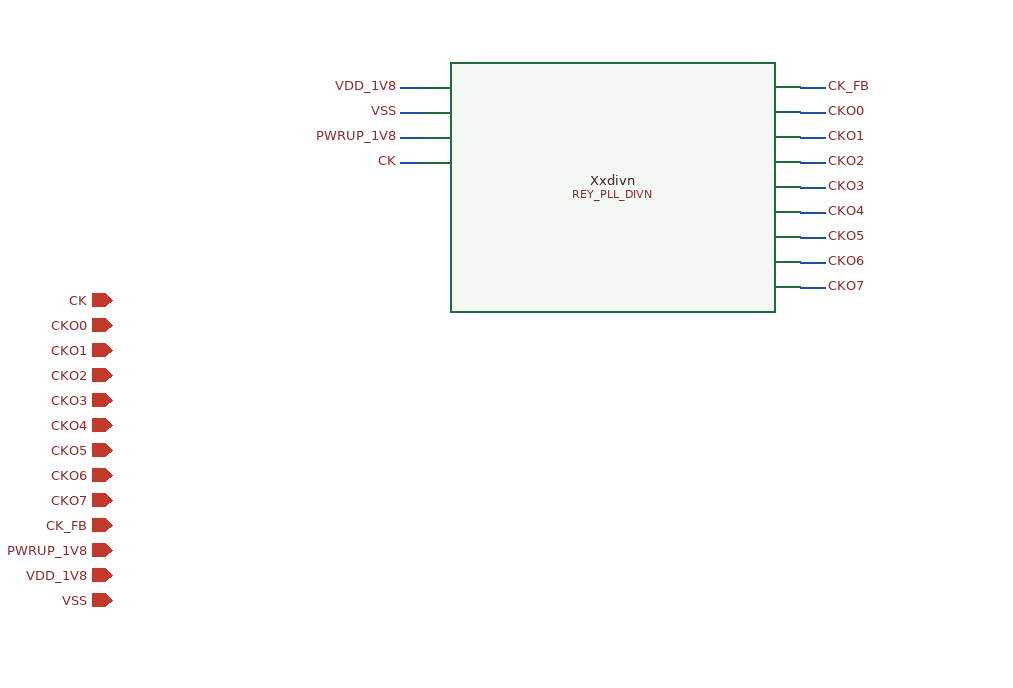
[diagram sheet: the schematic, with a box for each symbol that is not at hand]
v {xschem version=3.0.0 file_version=1.2 }
G {}
K {}
V {}
S {}
E {}
C {devices/iopin.sym} 0 0 0 0 {name=p0 lab=CK}
C {devices/iopin.sym} 0 20 0 0 {name=p1 lab=CKO0}
C {devices/iopin.sym} 0 40 0 0 {name=p2 lab=CKO1}
C {devices/iopin.sym} 0 60 0 0 {name=p3 lab=CKO2}
C {devices/iopin.sym} 0 80 0 0 {name=p4 lab=CKO3}
C {devices/iopin.sym} 0 100 0 0 {name=p5 lab=CKO4}
C {devices/iopin.sym} 0 120 0 0 {name=p6 lab=CKO5}
C {devices/iopin.sym} 0 140 0 0 {name=p7 lab=CKO6}
C {devices/iopin.sym} 0 160 0 0 {name=p8 lab=CKO7}
C {devices/iopin.sym} 0 180 0 0 {name=p9 lab=CK_FB}
C {devices/iopin.sym} 0 200 0 0 {name=p10 lab=PWRUP_1V8}
C {devices/iopin.sym} 0 220 0 0 {name=p11 lab=VDD_1V8}
C {devices/iopin.sym} 0 240 0 0 {name=p12 lab=VSS}
C {REY_PLL_SKY130A/REY_PLL_DIVN.sym} 400 0 0 0 {name=Xxdivn}
N 230.0 -170.0 250.0 -170.0 {lab=VDD_1V8}
C {devices/lab_pin.sym} 230.0 -170.0 0 0 {name=l0 sig_type=std_logic lab=VDD_1V8 }
N 230.0 -150.0 250.0 -150.0 {lab=VSS}
C {devices/lab_pin.sym} 230.0 -150.0 0 0 {name=l1 sig_type=std_logic lab=VSS }
N 230.0 -130.0 250.0 -130.0 {lab=PWRUP_1V8}
C {devices/lab_pin.sym} 230.0 -130.0 0 0 {name=l2 sig_type=std_logic lab=PWRUP_1V8 }
N 230.0 -110.0 250.0 -110.0 {lab=CK}
C {devices/lab_pin.sym} 230.0 -110.0 0 0 {name=l3 sig_type=std_logic lab=CK }
N 570.0 -170.0 550.0 -170.0 {lab=CK_FB}
C {devices/lab_pin.sym} 570.0 -170.0 2 0 {name=l4 sig_type=std_logic lab=CK_FB }
N 570.0 -150.0 550.0 -150.0 {lab=CKO0}
C {devices/lab_pin.sym} 570.0 -150.0 2 0 {name=l5 sig_type=std_logic lab=CKO0 }
N 570.0 -130.0 550.0 -130.0 {lab=CKO1}
C {devices/lab_pin.sym} 570.0 -130.0 2 0 {name=l6 sig_type=std_logic lab=CKO1 }
N 570.0 -110.0 550.0 -110.0 {lab=CKO2}
C {devices/lab_pin.sym} 570.0 -110.0 2 0 {name=l7 sig_type=std_logic lab=CKO2 }
N 570.0 -90.0 550.0 -90.0 {lab=CKO3}
C {devices/lab_pin.sym} 570.0 -90.0 2 0 {name=l8 sig_type=std_logic lab=CKO3 }
N 570.0 -70.0 550.0 -70.0 {lab=CKO4}
C {devices/lab_pin.sym} 570.0 -70.0 2 0 {name=l9 sig_type=std_logic lab=CKO4 }
N 570.0 -50.0 550.0 -50.0 {lab=CKO5}
C {devices/lab_pin.sym} 570.0 -50.0 2 0 {name=l10 sig_type=std_logic lab=CKO5 }
N 570.0 -30.0 550.0 -30.0 {lab=CKO6}
C {devices/lab_pin.sym} 570.0 -30.0 2 0 {name=l11 sig_type=std_logic lab=CKO6 }
N 570.0 -10.0 550.0 -10.0 {lab=CKO7}
C {devices/lab_pin.sym} 570.0 -10.0 2 0 {name=l12 sig_type=std_logic lab=CKO7 }
